VERSION 5.7 ;
  NOWIREEXTENSIONATPIN ON ;
  DIVIDERCHAR "/" ;
  BUSBITCHARS "[]" ;
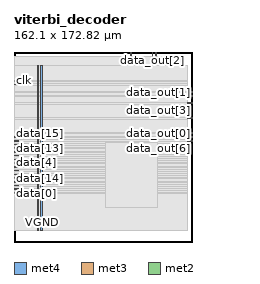
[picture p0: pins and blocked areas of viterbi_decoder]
MACRO viterbi_decoder
  CLASS BLOCK ;
  FOREIGN viterbi_decoder ;
  ORIGIN 0.000 0.000 ;
  SIZE 162.100 BY 172.820 ;
  PIN VGND
    DIRECTION INOUT ;
    USE GROUND ;
    PORT
      LAYER met4 ;
        RECT 24.340 10.640 25.940 160.720 ;
    END
  END VGND
  PIN VPWR
    DIRECTION INOUT ;
    USE POWER ;
    PORT
      LAYER met4 ;
        RECT 21.040 10.640 22.640 160.720 ;
    END
  END VPWR
  PIN clk
    DIRECTION INPUT ;
    USE SIGNAL ;
    ANTENNAGATEAREA 0.852000 ;
    PORT
      LAYER met3 ;
        RECT 0.000 146.240 4.000 146.840 ;
    END
  END clk
  PIN data[0]
    DIRECTION INPUT ;
    USE SIGNAL ;
    ANTENNAGATEAREA 0.196500 ;
    PORT
      LAYER met3 ;
        RECT 0.000 44.240 4.000 44.840 ;
    END
  END data[0]
  PIN data[10]
    DIRECTION INPUT ;
    USE SIGNAL ;
    ANTENNAGATEAREA 0.196500 ;
    PORT
      LAYER met3 ;
        RECT 0.000 47.640 4.000 48.240 ;
    END
  END data[10]
  PIN data[11]
    DIRECTION INPUT ;
    USE SIGNAL ;
    ANTENNAGATEAREA 0.196500 ;
    PORT
      LAYER met3 ;
        RECT 0.000 95.240 4.000 95.840 ;
    END
  END data[11]
  PIN data[12]
    DIRECTION INPUT ;
    USE SIGNAL ;
    ANTENNAGATEAREA 0.196500 ;
    PORT
      LAYER met3 ;
        RECT 0.000 54.440 4.000 55.040 ;
    END
  END data[12]
  PIN data[13]
    DIRECTION INPUT ;
    USE SIGNAL ;
    ANTENNAGATEAREA 0.196500 ;
    PORT
      LAYER met3 ;
        RECT 0.000 85.040 4.000 85.640 ;
    END
  END data[13]
  PIN data[14]
    DIRECTION INPUT ;
    USE SIGNAL ;
    ANTENNAGATEAREA 0.196500 ;
    PORT
      LAYER met3 ;
        RECT 0.000 57.840 4.000 58.440 ;
    END
  END data[14]
  PIN data[15]
    DIRECTION INPUT ;
    USE SIGNAL ;
    ANTENNAGATEAREA 0.196500 ;
    PORT
      LAYER met3 ;
        RECT 0.000 91.840 4.000 92.440 ;
    END
  END data[15]
  PIN data[1]
    DIRECTION INPUT ;
    USE SIGNAL ;
    ANTENNAGATEAREA 0.196500 ;
    PORT
      LAYER met3 ;
        RECT 0.000 71.440 4.000 72.040 ;
    END
  END data[1]
  PIN data[2]
    DIRECTION INPUT ;
    USE SIGNAL ;
    ANTENNAGATEAREA 0.196500 ;
    PORT
      LAYER met3 ;
        RECT 0.000 68.040 4.000 68.640 ;
    END
  END data[2]
  PIN data[3]
    DIRECTION INPUT ;
    USE SIGNAL ;
    ANTENNAGATEAREA 0.196500 ;
    PORT
      LAYER met3 ;
        RECT 0.000 74.840 4.000 75.440 ;
    END
  END data[3]
  PIN data[4]
    DIRECTION INPUT ;
    USE SIGNAL ;
    ANTENNAGATEAREA 0.196500 ;
    PORT
      LAYER met3 ;
        RECT 0.000 64.640 4.000 65.240 ;
    END
  END data[4]
  PIN data[5]
    DIRECTION INPUT ;
    USE SIGNAL ;
    ANTENNAGATEAREA 0.196500 ;
    PORT
      LAYER met3 ;
        RECT 0.000 81.640 4.000 82.240 ;
    END
  END data[5]
  PIN data[6]
    DIRECTION INPUT ;
    USE SIGNAL ;
    ANTENNAGATEAREA 0.196500 ;
    PORT
      LAYER met3 ;
        RECT 0.000 61.240 4.000 61.840 ;
    END
  END data[6]
  PIN data[7]
    DIRECTION INPUT ;
    USE SIGNAL ;
    ANTENNAGATEAREA 0.196500 ;
    PORT
      LAYER met3 ;
        RECT 0.000 78.240 4.000 78.840 ;
    END
  END data[7]
  PIN data[8]
    DIRECTION INPUT ;
    USE SIGNAL ;
    ANTENNAGATEAREA 0.196500 ;
    PORT
      LAYER met3 ;
        RECT 0.000 51.040 4.000 51.640 ;
    END
  END data[8]
  PIN data[9]
    DIRECTION INPUT ;
    USE SIGNAL ;
    ANTENNAGATEAREA 0.196500 ;
    PORT
      LAYER met3 ;
        RECT 0.000 88.440 4.000 89.040 ;
    END
  END data[9]
  PIN data_out[0]
    DIRECTION OUTPUT ;
    USE SIGNAL ;
    ANTENNADIFFAREA 0.445500 ;
    PORT
      LAYER met3 ;
        RECT 158.100 98.640 162.100 99.240 ;
    END
  END data_out[0]
  PIN data_out[1]
    DIRECTION OUTPUT ;
    USE SIGNAL ;
    ANTENNADIFFAREA 0.445500 ;
    PORT
      LAYER met3 ;
        RECT 158.100 136.040 162.100 136.640 ;
    END
  END data_out[1]
  PIN data_out[2]
    DIRECTION OUTPUT ;
    USE SIGNAL ;
    ANTENNADIFFAREA 0.445500 ;
    PORT
      LAYER met2 ;
        RECT 125.670 168.820 125.950 172.820 ;
    END
  END data_out[2]
  PIN data_out[3]
    DIRECTION OUTPUT ;
    USE SIGNAL ;
    ANTENNADIFFAREA 0.445500 ;
    PORT
      LAYER met3 ;
        RECT 158.100 125.840 162.100 126.440 ;
    END
  END data_out[3]
  PIN data_out[4]
    DIRECTION OUTPUT ;
    USE SIGNAL ;
    ANTENNADIFFAREA 0.445500 ;
    PORT
      LAYER met2 ;
        RECT 128.890 168.820 129.170 172.820 ;
    END
  END data_out[4]
  PIN data_out[5]
    DIRECTION OUTPUT ;
    USE SIGNAL ;
    ANTENNADIFFAREA 0.445500 ;
    PORT
      LAYER met3 ;
        RECT 158.100 132.640 162.100 133.240 ;
    END
  END data_out[5]
  PIN data_out[6]
    DIRECTION OUTPUT ;
    USE SIGNAL ;
    ANTENNADIFFAREA 0.445500 ;
    PORT
      LAYER met3 ;
        RECT 158.100 91.840 162.100 92.440 ;
    END
  END data_out[6]
  PIN data_out[7]
    DIRECTION OUTPUT ;
    USE SIGNAL ;
    ANTENNADIFFAREA 0.445500 ;
    PORT
      LAYER met3 ;
        RECT 158.100 112.240 162.100 112.840 ;
    END
  END data_out[7]
  PIN done_flag
    DIRECTION OUTPUT ;
    USE SIGNAL ;
    ANTENNADIFFAREA 0.445500 ;
    PORT
      LAYER met3 ;
        RECT 158.100 95.240 162.100 95.840 ;
    END
  END done_flag
  PIN en
    DIRECTION INPUT ;
    USE SIGNAL ;
    ANTENNAGATEAREA 0.213000 ;
    PORT
      LAYER met2 ;
        RECT 106.350 168.820 106.630 172.820 ;
    END
  END en
  PIN rst
    DIRECTION INPUT ;
    USE SIGNAL ;
    ANTENNAGATEAREA 0.213000 ;
    PORT
      LAYER met3 ;
        RECT 0.000 142.840 4.000 143.440 ;
    END
  END rst
  OBS
      LAYER nwell ;
        RECT 5.330 10.795 156.590 160.670 ;
      LAYER li1 ;
        RECT 5.520 10.795 156.400 160.565 ;
      LAYER met1 ;
        RECT 0.530 10.640 156.400 160.720 ;
      LAYER met2 ;
        RECT 0.550 168.540 106.070 168.820 ;
        RECT 106.910 168.540 125.390 168.820 ;
        RECT 126.230 168.540 128.610 168.820 ;
        RECT 129.450 168.540 154.920 168.820 ;
        RECT 0.550 10.695 154.920 168.540 ;
      LAYER met3 ;
        RECT 0.525 147.240 158.100 160.645 ;
        RECT 4.400 145.840 158.100 147.240 ;
        RECT 0.525 143.840 158.100 145.840 ;
        RECT 4.400 142.440 158.100 143.840 ;
        RECT 0.525 137.040 158.100 142.440 ;
        RECT 0.525 135.640 157.700 137.040 ;
        RECT 0.525 133.640 158.100 135.640 ;
        RECT 0.525 132.240 157.700 133.640 ;
        RECT 0.525 126.840 158.100 132.240 ;
        RECT 0.525 125.440 157.700 126.840 ;
        RECT 0.525 113.240 158.100 125.440 ;
        RECT 0.525 111.840 157.700 113.240 ;
        RECT 0.525 99.640 158.100 111.840 ;
        RECT 0.525 98.240 157.700 99.640 ;
        RECT 0.525 96.240 158.100 98.240 ;
        RECT 4.400 94.840 157.700 96.240 ;
        RECT 0.525 92.840 158.100 94.840 ;
        RECT 4.400 91.440 157.700 92.840 ;
        RECT 0.525 89.440 158.100 91.440 ;
        RECT 4.400 88.040 158.100 89.440 ;
        RECT 0.525 86.040 158.100 88.040 ;
        RECT 4.400 84.640 158.100 86.040 ;
        RECT 0.525 82.640 158.100 84.640 ;
        RECT 4.400 81.240 158.100 82.640 ;
        RECT 0.525 79.240 158.100 81.240 ;
        RECT 4.400 77.840 158.100 79.240 ;
        RECT 0.525 75.840 158.100 77.840 ;
        RECT 4.400 74.440 158.100 75.840 ;
        RECT 0.525 72.440 158.100 74.440 ;
        RECT 4.400 71.040 158.100 72.440 ;
        RECT 0.525 69.040 158.100 71.040 ;
        RECT 4.400 67.640 158.100 69.040 ;
        RECT 0.525 65.640 158.100 67.640 ;
        RECT 4.400 64.240 158.100 65.640 ;
        RECT 0.525 62.240 158.100 64.240 ;
        RECT 4.400 60.840 158.100 62.240 ;
        RECT 0.525 58.840 158.100 60.840 ;
        RECT 4.400 57.440 158.100 58.840 ;
        RECT 0.525 55.440 158.100 57.440 ;
        RECT 4.400 54.040 158.100 55.440 ;
        RECT 0.525 52.040 158.100 54.040 ;
        RECT 4.400 50.640 158.100 52.040 ;
        RECT 0.525 48.640 158.100 50.640 ;
        RECT 4.400 47.240 158.100 48.640 ;
        RECT 0.525 45.240 158.100 47.240 ;
        RECT 4.400 43.840 158.100 45.240 ;
        RECT 0.525 10.715 158.100 43.840 ;
      LAYER met4 ;
        RECT 83.095 31.455 130.345 90.265 ;
  END
END viterbi_decoder
END LIBRARY

